VERSION 5.7 ;
  NOWIREEXTENSIONATPIN ON ;
  DIVIDERCHAR "/" ;
  BUSBITCHARS "[]" ;
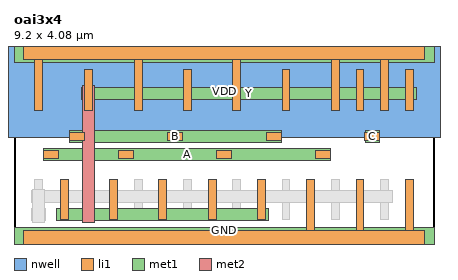
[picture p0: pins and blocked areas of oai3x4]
MACRO oai3x4
  CLASS BLOCK ;
  FOREIGN oai3x4 ;
  ORIGIN 0.000 0.000 ;
  SIZE 9.200 BY 4.080 ;
  PIN VDD
    ANTENNADIFFAREA 3.970600 ;
    PORT
      LAYER nwell ;
        RECT -0.230 2.200 9.430 4.410 ;
      LAYER li1 ;
        RECT 0.210 3.915 8.990 4.245 ;
        RECT 0.455 2.800 0.625 3.915 ;
        RECT 2.635 2.800 2.805 3.915 ;
        RECT 4.795 2.800 4.965 3.915 ;
        RECT 6.955 2.800 7.125 3.915 ;
        RECT 8.035 2.800 8.205 3.915 ;
      LAYER met1 ;
        RECT 0.000 3.840 9.200 4.320 ;
    END
  END VDD
  PIN GND
    ANTENNADIFFAREA 3.273400 ;
    PORT
      LAYER li1 ;
        RECT 6.415 0.165 6.585 1.280 ;
        RECT 7.495 0.165 7.665 1.280 ;
        RECT 8.575 0.165 8.745 1.280 ;
        RECT 0.210 -0.165 8.990 0.165 ;
      LAYER met1 ;
        RECT 0.000 -0.240 9.200 0.240 ;
    END
  END GND
  PIN A
    ANTENNAGATEAREA 2.100000 ;
    PORT
      LAYER li1 ;
        RECT 0.645 1.745 0.975 1.915 ;
        RECT 2.285 1.745 2.615 1.915 ;
        RECT 4.445 1.745 4.775 1.915 ;
        RECT 6.605 1.745 6.935 1.915 ;
      LAYER met1 ;
        RECT 0.650 1.700 6.930 1.960 ;
    END
  END A
  PIN B
    ANTENNAGATEAREA 2.100000 ;
    PORT
      LAYER li1 ;
        RECT 1.205 2.145 1.535 2.315 ;
        RECT 3.365 2.145 3.695 2.315 ;
        RECT 5.525 2.145 5.855 2.315 ;
      LAYER met1 ;
        RECT 1.210 2.100 5.850 2.360 ;
    END
  END B
  PIN C
    ANTENNAGATEAREA 1.596000 ;
    PORT
      LAYER li1 ;
        RECT 7.685 2.145 8.015 2.315 ;
      LAYER met1 ;
        RECT 7.690 2.100 8.010 2.360 ;
    END
  END C
  PIN Y
    ANTENNADIFFAREA 2.599800 ;
    PORT
      LAYER li1 ;
        RECT 1.555 2.800 1.725 3.680 ;
        RECT 3.715 2.800 3.885 3.680 ;
        RECT 5.875 2.800 6.045 3.680 ;
        RECT 7.495 2.800 7.665 3.680 ;
        RECT 8.575 2.800 8.745 3.680 ;
        RECT 1.015 0.400 1.185 1.280 ;
        RECT 2.095 0.400 2.265 1.280 ;
        RECT 3.175 0.400 3.345 1.280 ;
        RECT 4.255 0.400 4.425 1.280 ;
        RECT 5.335 0.400 5.505 1.280 ;
      LAYER met1 ;
        RECT 1.480 3.040 8.820 3.300 ;
        RECT 0.940 0.380 5.580 0.640 ;
      LAYER met2 ;
        RECT 1.510 0.350 1.770 3.330 ;
    END
  END Y
  OBS
      LAYER li1 ;
        RECT 1.015 2.800 1.185 3.680 ;
        RECT 2.095 2.800 2.265 3.680 ;
        RECT 3.175 2.800 3.345 3.680 ;
        RECT 4.255 2.800 4.425 3.680 ;
        RECT 5.335 2.800 5.505 3.680 ;
        RECT 6.415 2.800 6.585 3.680 ;
        RECT 0.455 0.400 0.625 1.280 ;
        RECT 1.555 0.400 1.725 1.280 ;
        RECT 2.635 0.400 2.805 1.280 ;
        RECT 3.715 0.400 3.885 1.280 ;
        RECT 4.795 0.400 4.965 1.280 ;
        RECT 5.875 0.400 6.045 1.280 ;
        RECT 6.955 0.400 7.125 1.280 ;
        RECT 8.035 0.400 8.205 1.280 ;
      LAYER met1 ;
        RECT 0.940 3.440 6.660 3.700 ;
        RECT 0.940 3.040 1.260 3.300 ;
        RECT 0.380 0.780 8.280 1.040 ;
        RECT 0.380 0.380 0.700 0.640 ;
      LAYER met2 ;
        RECT 0.970 3.010 1.230 3.730 ;
        RECT 0.410 0.350 0.670 1.070 ;
  END
END oai3x4
END LIBRARY

